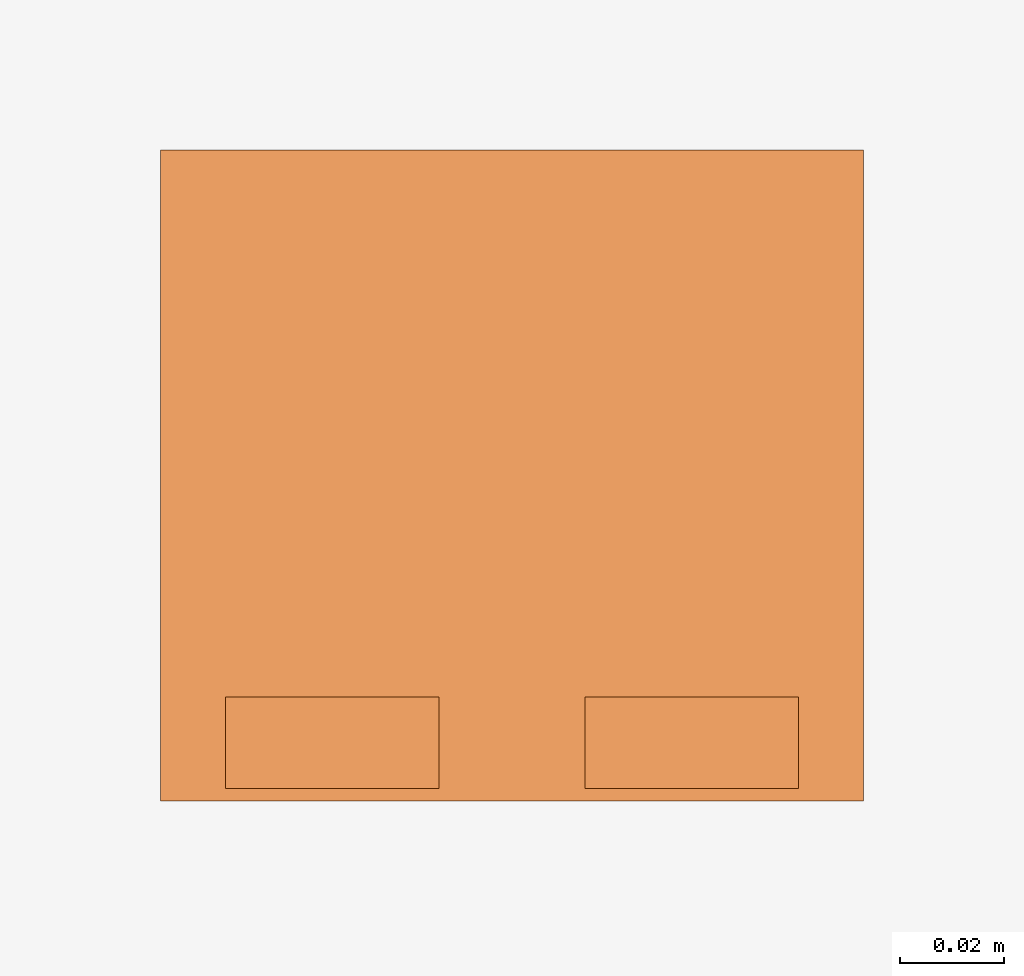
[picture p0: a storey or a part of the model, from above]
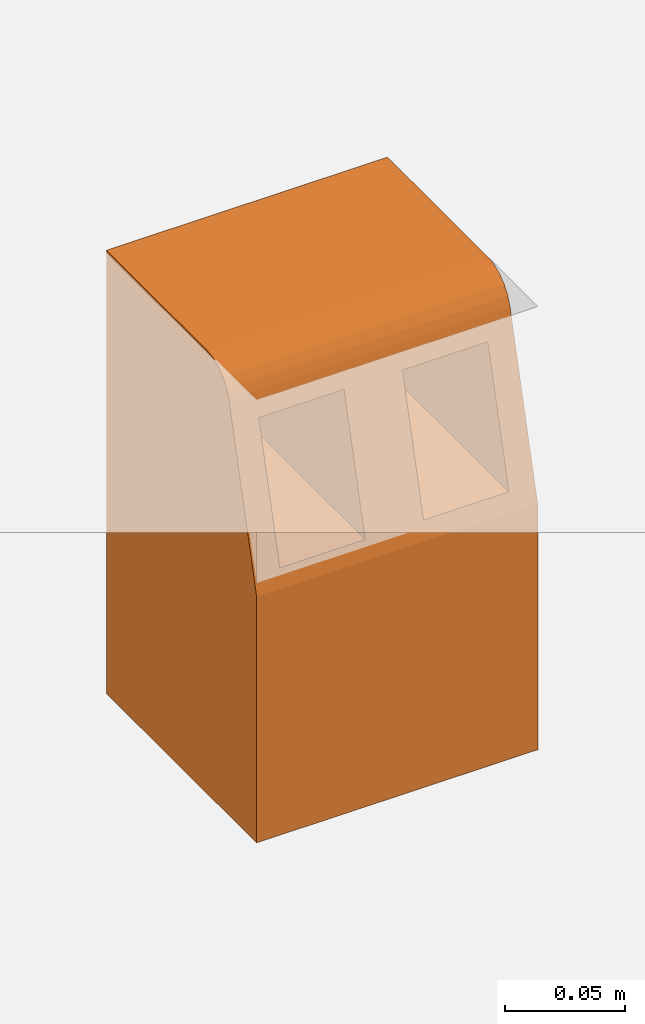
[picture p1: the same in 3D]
Properties of the parts of a building model (IFC2X3)

# File
Description: ViewDefinition [CoordinationView]
File name: 23452 - CFD kerb Outlet Half Batter.ifc
Time: 2013-10-16T12:21:53
Written by: Autodesk Revit 2013
Made in: 20120221_2030(x64)

# IfcProject, Project Number
LongName: Project Name; Phase: Project Status

# IfcSite, Default
RefLatitude: 42, 21, 30, 344238; RefLongitude: -71, -3, -35, -194702; RefElevation: 0 mm

# IfcBuilding
Pset_BuildingCommon - NumberOfStoreys: 1
Other - Project Number: Project Number; Project Issue Date: Issue Date; Project Address: ## Street City, State Zip; Project Status: Project Status; Project Name: Project Name; Client Name: Owner

# IfcBuildingStorey, Level 1
LongName: Level 1; Elevation: 0 mm
Graphics - Symbol at End 2 Default: yes; Line Weight: 1; Symbol at End 1 Default: no; Color: 0; Symbol: M_Level Head - Circle: M_Level Head - Circle; Line Pattern: Center
Constraints - Elevation Base: 0; Elevation: 0 mm
Identity Data - Structural: no; Building Story: yes; Name: Level 1
Dimensions - Computation Height: 0 mm

# IfcBuildingElementProxy: 23452 - CFD kerb Outlet Half Batter, Civil-Drainage-Channel-ACO-MultiDrain-M100D-Channel-System:23452 - CFD kerb Outlet Half Batter:23452 - CFD kerb Outlet Half Batter:1089344
In: Level 1
Material: Grey Polymer Concrete
Phasing - Phase Created: New Construction
Construction - 23406 - Grating - Solid Cover - Ductile Iron - 500mm Long: no; 23409 - Grating - ATec coated - Heelguard™ - Ductile Iron - 500mm Long: no; 12667 - Grating - Perforated - Galvanised Steel - 500mm Long: no; 12666 - Grating - Perforated - Galvanised Steel - 1000mm Long: no; 12611 - Grating - Slotted - Galvanised Steel - 500mm Long: no; 12657 - Grating - Perforated - Galvanised Steel - 500mm long: no; 12615 - Grating - Slotted - Galvanised Steel - 500mm Long: no; 12610 - Grating - Slotted - Galvanised Steel - 1000mm Long: no; 12656 - Grating - Perforated - Galvanised Steel - 1000mm long: no; 12680 - Grating - Heelguard™ - Composite Black - 500mm Long: no; 12619 - Grating - Mesh - Galvanised Steel - 500mm Long: no; 12673 - Grating - Intercept - Ductile Iron - 500mm Long: no; 12618 - Grating - Mesh - Galvanised Steel - 1000mm Long: no; 23405 - Grating - Heelguard™ - Ductile Iron - 500mm Long: no; 23404 - Universal Endcap - Female End: no; 23408 - Grating - Slotted - Ductile Iron - 500mm Long: no; 23404 - Universal Endcap - Male End: no; 12614 - Grating - Slotted - Galvanised Steel - 1000mm Long: no; 23452 - Kerb Outlet Half Batter: yes; Constant Depth Channel: no; Shallow Depth Channel: no; 23453 - Kerb Outlet Bull Nose: no; Sloping Channel: no; Shallow Depth Channel with seal: no; 23450 - Downpipe connector 75mm Depth: no; Grating 1000mm: no; Sump Unit: no; Constant Depth Junction Channel: no; 23451 - Downpipe connector 100mm Depth: no
Dimensions - Volume: 3063071 mm3; Length: 125 mm; EndCap Position: 125 mm; Custom_Value_Length: 875 mm; FloorCut_Length: -125 mm; SlopingInvertDepth: 125 mm; EndCap_Height: 249 mm; InvDepth: 80 mm; Length Drain: -1000 mm; SlopingEndOverallDepth: 200 mm; Depth: 150 mm; EndCap_Female_Height: 249 mm; Endcap_Void_Depth: 6000 mm; SlopingOverallDepth: 195 mm; ShallowOverallDepth: 75 mm; ShallowInvDepth: 55 mm; FloorCut_HorPosition: 67.5 mm; FloorCut_Depth: 225 mm; SlopingEndInvertDepth: 130 mm; FloorCut_Width: 135 mm
Constraints - Moves With Nearby Elements: no; Level: Level: Level 1
Pset_BuildingElementProxyCommon - Reference: 23452 - CFD kerb Outlet Half Batter
Materials and Finishes - Channel Colour: Grey; Edge Rail Material: N/A; Edge Rail Finish: N/A; Channel Material: Vienite® Synthetic Resin Concrete; Edge Rail Colour: N/A
Identity Data - Product Page URL: http://www.aco.co.uk/product_detail.php?id=15; Assembly Code: D2040; Watermarked By: www.aco.co.uk; OmniClass Number: 23.70.50.24; OmniClass Title: Rainwater Removal; Type Comments: ACO MultiDrain M100D CFD Kerb Outlet Half Batter Grey; Product Code: 23452; Assembly Description: Rain Water Drainage; Watermark 1: This file is the property of ACO Technologies PLC; Price: POA - contact ACO; Watermark 2: This file is watermarked and users are prohibited to reproduce, adapt, distribute this information; Installation guidelines: http://www.aco.co.uk/download.php?id=173; e-mail Sales: customersupport@aco.co.uk; Address: ACO Business Park, Hitchin Road, Shefford, Bedfordshire, United Kingdom SG17 5TE; Maintenance guidelines: http://www.aco.co.uk/download.php?id=173; Product brochure: http://www.aco.co.uk/download.php?id=173; Watermarked With: BIM Manager Premium Suite; Manufacturer: ACO Technologies plc - ACO Water Management Division; Cost: 0; Model Description: Channel drainage system; e-mail Technical: technical@aco.co.uk; Fax: +44 (0)1462 815895; Telephone: +44 (0)1462 816666; Model: ACO MultiDrain MD - M100D; URL: www.aco.co.uk
General - SerialNumber: 0; TagNumber: 0
Model Properties - Grating Product code 12610: N/A; Grating Product code 12611: N/A; Grating Product code 12614: N/A; Grating Product code 12667: N/A; Grating Product code 12680: N/A; Grating Product code 23408: N/A; End Cap Product code 23404: N/A; Grating Product code 12618: N/A; Grating Product code 12656: N/A; Grating Product code 12615: N/A; Grating Product code 12666: N/A; Grating Product code 23405: N/A; Grating Product code 12673: N/A; Grating Product code 12619: N/A; Grating Product code 12657: N/A; Grating Product code 23406: N/A
Green Building Properties - Edge Rail Recycled Material Content: N/A; Channel Recycled Material Content: 20% minimum; Channel Recyclable: Fully recyclable; Edge Rail Recyclable: N/A
Other - Revision: 1; CreatedBy: www.aco.co.uk
Data - Concrete Surround Volume - Load Class A 15 - Concrete Pavement: N/A; Invert Depth: N/A; Product Dimensions: 125mm x 135mm x225mm (LxWxH); Product Standard: N/A; Pre-formed Outlet Ø: N/A; Load Class: N/A; Concrete Surround Volume - Load Class D 400 - Concrete Pavement: N/A; Concrete Surround Volume - Load Class B 125 - C 250 - Concrete Pavement: N/A; ACO Hydraulic Design Software: N/A; Installation - Concrete Grade: N/A; Hydraulic Performance: N/A; Product Weight: 6.7kg; Channel C.S.A: N/A

# IfcOpeningElement: Recess
In: Level 1
Dimensions - Thickness: 400 mm; Area: 27030000 mm2; Perimeter: 20800 mm; Volume: 10808203125 mm3
Structural - Structural: no; Enable Analytical Model: no
Phasing - Phase Created: New Construction
Constraints - Height Offset From Level: 0 mm; Room Bounding: yes; Related to Mass: no; Level: Level: Level 1
Construction - Function: 0; Default Thickness: 400 mm
Analytical Properties - Roughness: 1; Absorptance: 0.1
Graphics - Coarse Scale Fill Color: 0
Materials and Finishes - Structural Material: Plant

# IfcSlab: Floor:Generic Floor - 400mm, Floor:Generic Floor - 400mm:193825
In: Level 1
PredefinedType: FLOOR; Material: Plant 400 mm
Dimensions - Thickness: 400 mm; Area: 27030000 mm2; Perimeter: 20800 mm; Volume: 10808203125 mm3
Structural - Structural: no; Enable Analytical Model: no
Phasing - Phase Created: New Construction
Constraints - Height Offset From Level: 0 mm; Room Bounding: yes; Related to Mass: no; Level: Level: Level 1
Pset_SlabCommon - Reference: Generic Floor - 400mm; IsExternal: no; LoadBearing: yes
Construction - Function: 0; Default Thickness: 400 mm
Analytical Properties - Roughness: 1; Absorptance: 0.1
Graphics - Coarse Scale Fill Color: 0
Materials and Finishes - Structural Material: Plant
